VERSION 5.7 ;
BUSBITCHARS "[]" ;
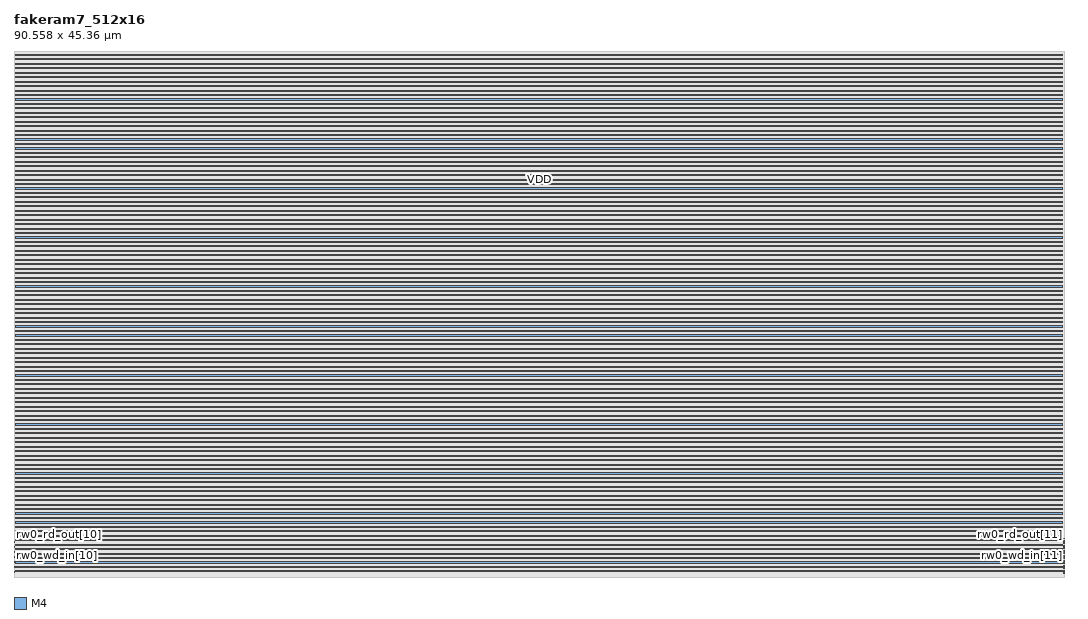
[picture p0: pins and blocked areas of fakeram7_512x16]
MACRO fakeram7_512x16
  FOREIGN fakeram7_512x16 0 0 ;
  SYMMETRY X Y R90 ;
  SIZE 90.558 BY 45.360 ;
  CLASS BLOCK ;
  PIN rw0_clk
    DIRECTION INPUT ;
    USE SIGNAL ;
    SHAPE ABUTMENT ;
    PORT
      LAYER M4 ;
      RECT 0.000 0.276 0.072 0.300 ;
    END
  END rw0_clk
  PIN rw0_ce_in
    DIRECTION INPUT ;
    USE SIGNAL ;
    SHAPE ABUTMENT ;
    PORT
      LAYER M4 ;
      RECT 90.486 0.276 90.558 0.300 ;
    END
  END rw0_ce_in
  PIN rw0_we_in
    DIRECTION INPUT ;
    USE SIGNAL ;
    SHAPE ABUTMENT ;
    PORT
      LAYER M4 ;
      RECT 0.000 0.420 0.072 0.444 ;
    END
  END rw0_we_in
  PIN rw0_addr_in[0]
    DIRECTION INPUT ;
    USE SIGNAL ;
    SHAPE ABUTMENT ;
    PORT
      LAYER M4 ;
      RECT 90.486 0.420 90.558 0.444 ;
    END
  END rw0_addr_in[0]
  PIN rw0_addr_in[1]
    DIRECTION INPUT ;
    USE SIGNAL ;
    SHAPE ABUTMENT ;
    PORT
      LAYER M4 ;
      RECT 0.000 0.564 0.072 0.588 ;
    END
  END rw0_addr_in[1]
  PIN rw0_addr_in[2]
    DIRECTION INPUT ;
    USE SIGNAL ;
    SHAPE ABUTMENT ;
    PORT
      LAYER M4 ;
      RECT 90.486 0.564 90.558 0.588 ;
    END
  END rw0_addr_in[2]
  PIN rw0_addr_in[3]
    DIRECTION INPUT ;
    USE SIGNAL ;
    SHAPE ABUTMENT ;
    PORT
      LAYER M4 ;
      RECT 0.000 0.708 0.072 0.732 ;
    END
  END rw0_addr_in[3]
  PIN rw0_addr_in[4]
    DIRECTION INPUT ;
    USE SIGNAL ;
    SHAPE ABUTMENT ;
    PORT
      LAYER M4 ;
      RECT 90.486 0.708 90.558 0.732 ;
    END
  END rw0_addr_in[4]
  PIN rw0_addr_in[5]
    DIRECTION INPUT ;
    USE SIGNAL ;
    SHAPE ABUTMENT ;
    PORT
      LAYER M4 ;
      RECT 0.000 0.852 0.072 0.876 ;
    END
  END rw0_addr_in[5]
  PIN rw0_addr_in[6]
    DIRECTION INPUT ;
    USE SIGNAL ;
    SHAPE ABUTMENT ;
    PORT
      LAYER M4 ;
      RECT 90.486 0.852 90.558 0.876 ;
    END
  END rw0_addr_in[6]
  PIN rw0_addr_in[7]
    DIRECTION INPUT ;
    USE SIGNAL ;
    SHAPE ABUTMENT ;
    PORT
      LAYER M4 ;
      RECT 0.000 0.996 0.072 1.020 ;
    END
  END rw0_addr_in[7]
  PIN rw0_addr_in[8]
    DIRECTION INPUT ;
    USE SIGNAL ;
    SHAPE ABUTMENT ;
    PORT
      LAYER M4 ;
      RECT 90.486 0.996 90.558 1.020 ;
    END
  END rw0_addr_in[8]
  PIN rw0_wd_in[0]
    DIRECTION INPUT ;
    USE SIGNAL ;
    SHAPE ABUTMENT ;
    PORT
      LAYER M4 ;
      RECT 0.000 1.140 0.072 1.164 ;
    END
  END rw0_wd_in[0]
  PIN rw0_wd_in[1]
    DIRECTION INPUT ;
    USE SIGNAL ;
    SHAPE ABUTMENT ;
    PORT
      LAYER M4 ;
      RECT 90.486 1.140 90.558 1.164 ;
    END
  END rw0_wd_in[1]
  PIN rw0_wd_in[2]
    DIRECTION INPUT ;
    USE SIGNAL ;
    SHAPE ABUTMENT ;
    PORT
      LAYER M4 ;
      RECT 0.000 1.284 0.072 1.308 ;
    END
  END rw0_wd_in[2]
  PIN rw0_wd_in[3]
    DIRECTION INPUT ;
    USE SIGNAL ;
    SHAPE ABUTMENT ;
    PORT
      LAYER M4 ;
      RECT 90.486 1.284 90.558 1.308 ;
    END
  END rw0_wd_in[3]
  PIN rw0_wd_in[4]
    DIRECTION INPUT ;
    USE SIGNAL ;
    SHAPE ABUTMENT ;
    PORT
      LAYER M4 ;
      RECT 0.000 1.428 0.072 1.452 ;
    END
  END rw0_wd_in[4]
  PIN rw0_wd_in[5]
    DIRECTION INPUT ;
    USE SIGNAL ;
    SHAPE ABUTMENT ;
    PORT
      LAYER M4 ;
      RECT 90.486 1.428 90.558 1.452 ;
    END
  END rw0_wd_in[5]
  PIN rw0_wd_in[6]
    DIRECTION INPUT ;
    USE SIGNAL ;
    SHAPE ABUTMENT ;
    PORT
      LAYER M4 ;
      RECT 0.000 1.572 0.072 1.596 ;
    END
  END rw0_wd_in[6]
  PIN rw0_wd_in[7]
    DIRECTION INPUT ;
    USE SIGNAL ;
    SHAPE ABUTMENT ;
    PORT
      LAYER M4 ;
      RECT 90.486 1.572 90.558 1.596 ;
    END
  END rw0_wd_in[7]
  PIN rw0_wd_in[8]
    DIRECTION INPUT ;
    USE SIGNAL ;
    SHAPE ABUTMENT ;
    PORT
      LAYER M4 ;
      RECT 0.000 1.716 0.072 1.740 ;
    END
  END rw0_wd_in[8]
  PIN rw0_wd_in[9]
    DIRECTION INPUT ;
    USE SIGNAL ;
    SHAPE ABUTMENT ;
    PORT
      LAYER M4 ;
      RECT 90.486 1.716 90.558 1.740 ;
    END
  END rw0_wd_in[9]
  PIN rw0_wd_in[10]
    DIRECTION INPUT ;
    USE SIGNAL ;
    SHAPE ABUTMENT ;
    PORT
      LAYER M4 ;
      RECT 0.000 1.860 0.072 1.884 ;
    END
  END rw0_wd_in[10]
  PIN rw0_wd_in[11]
    DIRECTION INPUT ;
    USE SIGNAL ;
    SHAPE ABUTMENT ;
    PORT
      LAYER M4 ;
      RECT 90.486 1.860 90.558 1.884 ;
    END
  END rw0_wd_in[11]
  PIN rw0_wd_in[12]
    DIRECTION INPUT ;
    USE SIGNAL ;
    SHAPE ABUTMENT ;
    PORT
      LAYER M4 ;
      RECT 0.000 2.004 0.072 2.028 ;
    END
  END rw0_wd_in[12]
  PIN rw0_wd_in[13]
    DIRECTION INPUT ;
    USE SIGNAL ;
    SHAPE ABUTMENT ;
    PORT
      LAYER M4 ;
      RECT 90.486 2.004 90.558 2.028 ;
    END
  END rw0_wd_in[13]
  PIN rw0_wd_in[14]
    DIRECTION INPUT ;
    USE SIGNAL ;
    SHAPE ABUTMENT ;
    PORT
      LAYER M4 ;
      RECT 0.000 2.148 0.072 2.172 ;
    END
  END rw0_wd_in[14]
  PIN rw0_wd_in[15]
    DIRECTION INPUT ;
    USE SIGNAL ;
    SHAPE ABUTMENT ;
    PORT
      LAYER M4 ;
      RECT 90.486 2.148 90.558 2.172 ;
    END
  END rw0_wd_in[15]
  PIN rw0_rd_out[0]
    DIRECTION OUTPUT ;
    USE SIGNAL ;
    SHAPE ABUTMENT ;
    PORT
      LAYER M4 ;
      RECT 0.000 2.292 0.072 2.316 ;
    END
  END rw0_rd_out[0]
  PIN rw0_rd_out[1]
    DIRECTION OUTPUT ;
    USE SIGNAL ;
    SHAPE ABUTMENT ;
    PORT
      LAYER M4 ;
      RECT 90.486 2.292 90.558 2.316 ;
    END
  END rw0_rd_out[1]
  PIN rw0_rd_out[2]
    DIRECTION OUTPUT ;
    USE SIGNAL ;
    SHAPE ABUTMENT ;
    PORT
      LAYER M4 ;
      RECT 0.000 2.436 0.072 2.460 ;
    END
  END rw0_rd_out[2]
  PIN rw0_rd_out[3]
    DIRECTION OUTPUT ;
    USE SIGNAL ;
    SHAPE ABUTMENT ;
    PORT
      LAYER M4 ;
      RECT 90.486 2.436 90.558 2.460 ;
    END
  END rw0_rd_out[3]
  PIN rw0_rd_out[4]
    DIRECTION OUTPUT ;
    USE SIGNAL ;
    SHAPE ABUTMENT ;
    PORT
      LAYER M4 ;
      RECT 0.000 2.580 0.072 2.604 ;
    END
  END rw0_rd_out[4]
  PIN rw0_rd_out[5]
    DIRECTION OUTPUT ;
    USE SIGNAL ;
    SHAPE ABUTMENT ;
    PORT
      LAYER M4 ;
      RECT 90.486 2.580 90.558 2.604 ;
    END
  END rw0_rd_out[5]
  PIN rw0_rd_out[6]
    DIRECTION OUTPUT ;
    USE SIGNAL ;
    SHAPE ABUTMENT ;
    PORT
      LAYER M4 ;
      RECT 0.000 2.724 0.072 2.748 ;
    END
  END rw0_rd_out[6]
  PIN rw0_rd_out[7]
    DIRECTION OUTPUT ;
    USE SIGNAL ;
    SHAPE ABUTMENT ;
    PORT
      LAYER M4 ;
      RECT 90.486 2.724 90.558 2.748 ;
    END
  END rw0_rd_out[7]
  PIN rw0_rd_out[8]
    DIRECTION OUTPUT ;
    USE SIGNAL ;
    SHAPE ABUTMENT ;
    PORT
      LAYER M4 ;
      RECT 0.000 2.868 0.072 2.892 ;
    END
  END rw0_rd_out[8]
  PIN rw0_rd_out[9]
    DIRECTION OUTPUT ;
    USE SIGNAL ;
    SHAPE ABUTMENT ;
    PORT
      LAYER M4 ;
      RECT 90.486 2.868 90.558 2.892 ;
    END
  END rw0_rd_out[9]
  PIN rw0_rd_out[10]
    DIRECTION OUTPUT ;
    USE SIGNAL ;
    SHAPE ABUTMENT ;
    PORT
      LAYER M4 ;
      RECT 0.000 3.012 0.072 3.036 ;
    END
  END rw0_rd_out[10]
  PIN rw0_rd_out[11]
    DIRECTION OUTPUT ;
    USE SIGNAL ;
    SHAPE ABUTMENT ;
    PORT
      LAYER M4 ;
      RECT 90.486 3.012 90.558 3.036 ;
    END
  END rw0_rd_out[11]
  PIN rw0_rd_out[12]
    DIRECTION OUTPUT ;
    USE SIGNAL ;
    SHAPE ABUTMENT ;
    PORT
      LAYER M4 ;
      RECT 0.000 3.156 0.072 3.180 ;
    END
  END rw0_rd_out[12]
  PIN rw0_rd_out[13]
    DIRECTION OUTPUT ;
    USE SIGNAL ;
    SHAPE ABUTMENT ;
    PORT
      LAYER M4 ;
      RECT 90.486 3.156 90.558 3.180 ;
    END
  END rw0_rd_out[13]
  PIN rw0_rd_out[14]
    DIRECTION OUTPUT ;
    USE SIGNAL ;
    SHAPE ABUTMENT ;
    PORT
      LAYER M4 ;
      RECT 0.000 3.300 0.072 3.324 ;
    END
  END rw0_rd_out[14]
  PIN rw0_rd_out[15]
    DIRECTION OUTPUT ;
    USE SIGNAL ;
    SHAPE ABUTMENT ;
    PORT
      LAYER M4 ;
      RECT 90.486 3.300 90.558 3.324 ;
    END
  END rw0_rd_out[15]
  PIN VDD
    DIRECTION INOUT ;
    USE POWER ;
    PORT
      LAYER M4 ;
      RECT 0.120 0.432 90.438 0.528 ;
      RECT 0.120 1.200 90.438 1.296 ;
      RECT 0.120 1.968 90.438 2.064 ;
      RECT 0.120 2.736 90.438 2.832 ;
      RECT 0.120 3.504 90.438 3.600 ;
      RECT 0.120 4.272 90.438 4.368 ;
      RECT 0.120 5.040 90.438 5.136 ;
      RECT 0.120 5.808 90.438 5.904 ;
      RECT 0.120 6.576 90.438 6.672 ;
      RECT 0.120 7.344 90.438 7.440 ;
      RECT 0.120 8.112 90.438 8.208 ;
      RECT 0.120 8.880 90.438 8.976 ;
      RECT 0.120 9.648 90.438 9.744 ;
      RECT 0.120 10.416 90.438 10.512 ;
      RECT 0.120 11.184 90.438 11.280 ;
      RECT 0.120 11.952 90.438 12.048 ;
      RECT 0.120 12.720 90.438 12.816 ;
      RECT 0.120 13.488 90.438 13.584 ;
      RECT 0.120 14.256 90.438 14.352 ;
      RECT 0.120 15.024 90.438 15.120 ;
      RECT 0.120 15.792 90.438 15.888 ;
      RECT 0.120 16.560 90.438 16.656 ;
      RECT 0.120 17.328 90.438 17.424 ;
      RECT 0.120 18.096 90.438 18.192 ;
      RECT 0.120 18.864 90.438 18.960 ;
      RECT 0.120 19.632 90.438 19.728 ;
      RECT 0.120 20.400 90.438 20.496 ;
      RECT 0.120 21.168 90.438 21.264 ;
      RECT 0.120 21.936 90.438 22.032 ;
      RECT 0.120 22.704 90.438 22.800 ;
      RECT 0.120 23.472 90.438 23.568 ;
      RECT 0.120 24.240 90.438 24.336 ;
      RECT 0.120 25.008 90.438 25.104 ;
      RECT 0.120 25.776 90.438 25.872 ;
      RECT 0.120 26.544 90.438 26.640 ;
      RECT 0.120 27.312 90.438 27.408 ;
      RECT 0.120 28.080 90.438 28.176 ;
      RECT 0.120 28.848 90.438 28.944 ;
      RECT 0.120 29.616 90.438 29.712 ;
      RECT 0.120 30.384 90.438 30.480 ;
      RECT 0.120 31.152 90.438 31.248 ;
      RECT 0.120 31.920 90.438 32.016 ;
      RECT 0.120 32.688 90.438 32.784 ;
      RECT 0.120 33.456 90.438 33.552 ;
      RECT 0.120 34.224 90.438 34.320 ;
      RECT 0.120 34.992 90.438 35.088 ;
      RECT 0.120 35.760 90.438 35.856 ;
      RECT 0.120 36.528 90.438 36.624 ;
      RECT 0.120 37.296 90.438 37.392 ;
      RECT 0.120 38.064 90.438 38.160 ;
      RECT 0.120 38.832 90.438 38.928 ;
      RECT 0.120 39.600 90.438 39.696 ;
      RECT 0.120 40.368 90.438 40.464 ;
      RECT 0.120 41.136 90.438 41.232 ;
      RECT 0.120 41.904 90.438 42.000 ;
      RECT 0.120 42.672 90.438 42.768 ;
      RECT 0.120 43.440 90.438 43.536 ;
      RECT 0.120 44.208 90.438 44.304 ;
      RECT 0.120 44.976 90.438 45.072 ;
    END
  END VDD
  PIN VSS
    DIRECTION INOUT ;
    USE GROUND ;
    PORT
      LAYER M4 ;
      RECT 0.120 0.816 90.438 0.912 ;
      RECT 0.120 1.584 90.438 1.680 ;
      RECT 0.120 2.352 90.438 2.448 ;
      RECT 0.120 3.120 90.438 3.216 ;
      RECT 0.120 3.888 90.438 3.984 ;
      RECT 0.120 4.656 90.438 4.752 ;
      RECT 0.120 5.424 90.438 5.520 ;
      RECT 0.120 6.192 90.438 6.288 ;
      RECT 0.120 6.960 90.438 7.056 ;
      RECT 0.120 7.728 90.438 7.824 ;
      RECT 0.120 8.496 90.438 8.592 ;
      RECT 0.120 9.264 90.438 9.360 ;
      RECT 0.120 10.032 90.438 10.128 ;
      RECT 0.120 10.800 90.438 10.896 ;
      RECT 0.120 11.568 90.438 11.664 ;
      RECT 0.120 12.336 90.438 12.432 ;
      RECT 0.120 13.104 90.438 13.200 ;
      RECT 0.120 13.872 90.438 13.968 ;
      RECT 0.120 14.640 90.438 14.736 ;
      RECT 0.120 15.408 90.438 15.504 ;
      RECT 0.120 16.176 90.438 16.272 ;
      RECT 0.120 16.944 90.438 17.040 ;
      RECT 0.120 17.712 90.438 17.808 ;
      RECT 0.120 18.480 90.438 18.576 ;
      RECT 0.120 19.248 90.438 19.344 ;
      RECT 0.120 20.016 90.438 20.112 ;
      RECT 0.120 20.784 90.438 20.880 ;
      RECT 0.120 21.552 90.438 21.648 ;
      RECT 0.120 22.320 90.438 22.416 ;
      RECT 0.120 23.088 90.438 23.184 ;
      RECT 0.120 23.856 90.438 23.952 ;
      RECT 0.120 24.624 90.438 24.720 ;
      RECT 0.120 25.392 90.438 25.488 ;
      RECT 0.120 26.160 90.438 26.256 ;
      RECT 0.120 26.928 90.438 27.024 ;
      RECT 0.120 27.696 90.438 27.792 ;
      RECT 0.120 28.464 90.438 28.560 ;
      RECT 0.120 29.232 90.438 29.328 ;
      RECT 0.120 30.000 90.438 30.096 ;
      RECT 0.120 30.768 90.438 30.864 ;
      RECT 0.120 31.536 90.438 31.632 ;
      RECT 0.120 32.304 90.438 32.400 ;
      RECT 0.120 33.072 90.438 33.168 ;
      RECT 0.120 33.840 90.438 33.936 ;
      RECT 0.120 34.608 90.438 34.704 ;
      RECT 0.120 35.376 90.438 35.472 ;
      RECT 0.120 36.144 90.438 36.240 ;
      RECT 0.120 36.912 90.438 37.008 ;
      RECT 0.120 37.680 90.438 37.776 ;
      RECT 0.120 38.448 90.438 38.544 ;
      RECT 0.120 39.216 90.438 39.312 ;
      RECT 0.120 39.984 90.438 40.080 ;
      RECT 0.120 40.752 90.438 40.848 ;
      RECT 0.120 41.520 90.438 41.616 ;
      RECT 0.120 42.288 90.438 42.384 ;
      RECT 0.120 43.056 90.438 43.152 ;
      RECT 0.120 43.824 90.438 43.920 ;
      RECT 0.120 44.592 90.438 44.688 ;
    END
  END VSS
  OBS
    LAYER M1 ;
      RECT 0.000 0.000 90.558 45.360 ;
    LAYER M2 ;
      RECT 0.000 0.000 90.558 45.360 ;
    LAYER M3 ;
      RECT 0.000 0.000 90.558 45.360 ;
  END
END fakeram7_512x16
END LIBRARY
